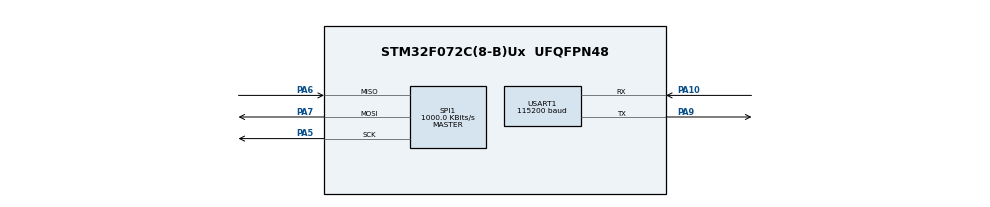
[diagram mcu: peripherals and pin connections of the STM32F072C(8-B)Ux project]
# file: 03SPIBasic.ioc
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Mcu.Family=STM32F0
Mcu.Name=STM32F072C(8-B)Ux
Mcu.Package=UFQFPN48
PA10.Mode=Asynchronous
PA10.Signal=USART1_RX
PA13.Mode=Serial_Wire
PA13.Signal=SYS_SWDIO
PA14.Mode=Serial_Wire
PA14.Signal=SYS_SWCLK
PA5.Mode=Full_Duplex_Master
PA5.Signal=SPI1_SCK
PA6.Mode=Full_Duplex_Master
PA6.Signal=SPI1_MISO
PA7.Mode=Full_Duplex_Master
PA7.Signal=SPI1_MOSI
PA9.Mode=Asynchronous
PA9.Signal=USART1_TX
ProjectManager.HeapSize=0x200
ProjectManager.StackSize=0x400
ProjectManager.TargetToolchain=CMake
RCC.SYSCLKFreq_VALUE=48000000
RCC.SYSCLKSource=RCC_SYSCLKSOURCE_HSI48
SPI1.BaudRatePrescaler=SPI_BAUDRATEPRESCALER_64
SPI1.CalculateBaudRate=1000.0 KBits/s
SPI1.Direction=SPI_DIRECTION_2LINES
SPI1.Mode=SPI_MODE_MASTER
SPI1.VirtualType=VM_MASTER
USART1.BaudRate=115200
USART1.VirtualMode-Asynchronous=VM_ASYNC
board=custom

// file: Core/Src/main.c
/* USER CODE BEGIN Header */
/**
  ******************************************************************************
  * @file           : main.c
  * @brief          : Main program body
  ******************************************************************************
  * @attention
  *
  * Copyright (c) 2026 STMicroelectronics.
  * All rights reserved.
  *
  * This software is licensed under terms that can be found in the LICENSE file
  * in the root directory of this software component.
  * If no LICENSE file comes with this software, it is provided AS-IS.
  *
  ******************************************************************************
  */
/* USER CODE END Header */
#include "main.h"

/* USER CODE BEGIN Includes */
#include <stdio.h>
#include <string.h>
/*
 * SPI1 全双工回环：主机、Mode 0（CPOL=0、CPHA=第一个边沿）、8 位、
 * MSB First、软件 NSS。HSI 8 MHz 经 8 分频后 SCK 约 1 MHz。
 * PA5=SCK、PA6=MISO、PA7=MOSI；测试时短接 PA6 与 PA7。
 */
/* USER CODE END Includes */

SPI_HandleTypeDef hspi1;

UART_HandleTypeDef huart1;

void SystemClock_Config(void);
static void MX_GPIO_Init(void);
static void MX_SPI1_Init(void);
static void MX_USART1_UART_Init(void);
/* USER CODE BEGIN PFP */
static void App_Init(void);
static void App_Loop(void);
/* USER CODE END PFP */

/* USER CODE BEGIN 0 */
/** @brief 通过 USART1 PA9 输出日志，阻塞发送超时为 100 ms。 */
int _write(int file,char *ptr,int len){(void)file;if(ptr==NULL||len<=0)return 0;return HAL_UART_Transmit(&huart1,(uint8_t*)ptr,(uint16_t)len,100U)==HAL_OK?len:-1;}
/** @brief SPI1 与 USART1 已由 CubeMX 初始化。 */
static void App_Init(void){}
/*
 * SPI 每移出一位也同时移入一位，所以 TX/RX 长度保持一致。
 * 100 ms 超时避免接线异常时永久等待；HAL 成功且八字节完全一致才 PASS。
 */
static void App_Loop(void){static const uint8_t tx[]={0x00,0x55,0xAA,0xFF,0x12,0x34,0x56,0x78};uint8_t rx[sizeof tx]={0};HAL_StatusTypeDef s=HAL_SPI_TransmitReceive(&hspi1,(uint8_t*)tx,rx,sizeof tx,100U);printf("\r\nSPI loopback test\r\nTX: 00 55 AA FF 12 34 56 78\r\nRX:");for(uint32_t i=0;i<sizeof rx;i++)printf(" %02X",rx[i]);printf("\r\nResult: %s\r\n",(s==HAL_OK&&memcmp(tx,rx,sizeof tx)==0)?"PASS":"FAIL");HAL_Delay(1000U);}
/* USER CODE END 0 */

int main(void)
{

  /* MCU Configuration--------------------------------------------------------*/

  /* Reset of all peripherals, Initializes the Flash interface and the Systick. */
  HAL_Init();

  /* Configure the system clock */
  SystemClock_Config();

  /* Initialize all configured peripherals */
  MX_GPIO_Init();
  MX_SPI1_Init();
  MX_USART1_UART_Init();
  /* USER CODE BEGIN 2 */
  App_Init();
  /* USER CODE END 2 */

  /* Infinite loop */
  /* USER CODE BEGIN WHILE */
  while (1)
  {
    App_Loop();
    /* USER CODE END WHILE */

  }
}

void SystemClock_Config(void)
{
  RCC_OscInitTypeDef RCC_OscInitStruct = {0};
  RCC_ClkInitTypeDef RCC_ClkInitStruct = {0};
  RCC_PeriphCLKInitTypeDef PeriphClkInit = {0};

  /** Initializes the RCC Oscillators according to the specified parameters
  * in the RCC_OscInitTypeDef structure.
  */
  RCC_OscInitStruct.OscillatorType = RCC_OSCILLATORTYPE_HSI;
  RCC_OscInitStruct.HSIState = RCC_HSI_ON;
  RCC_OscInitStruct.HSICalibrationValue = RCC_HSICALIBRATION_DEFAULT;
  RCC_OscInitStruct.PLL.PLLState = RCC_PLL_NONE;
  if (HAL_RCC_OscConfig(&RCC_OscInitStruct) != HAL_OK)
  {
    Error_Handler();
  }

  /** Initializes the CPU, AHB and APB buses clocks
  */
  RCC_ClkInitStruct.ClockType = RCC_CLOCKTYPE_HCLK|RCC_CLOCKTYPE_SYSCLK
                              |RCC_CLOCKTYPE_PCLK1;
  RCC_ClkInitStruct.SYSCLKSource = RCC_SYSCLKSOURCE_HSI;
  RCC_ClkInitStruct.AHBCLKDivider = RCC_SYSCLK_DIV1;
  RCC_ClkInitStruct.APB1CLKDivider = RCC_HCLK_DIV1;

  if (HAL_RCC_ClockConfig(&RCC_ClkInitStruct, FLASH_LATENCY_0) != HAL_OK)
  {
    Error_Handler();
  }
  PeriphClkInit.PeriphClockSelection = RCC_PERIPHCLK_USART1;
  PeriphClkInit.Usart1ClockSelection = RCC_USART1CLKSOURCE_PCLK1;
  if (HAL_RCCEx_PeriphCLKConfig(&PeriphClkInit) != HAL_OK)
  {
    Error_Handler();
  }
}

static void MX_SPI1_Init(void)
{

  /* SPI1 parameter configuration*/
  hspi1.Instance = SPI1;
  hspi1.Init.Mode = SPI_MODE_MASTER;
  hspi1.Init.Direction = SPI_DIRECTION_2LINES;
  hspi1.Init.DataSize = SPI_DATASIZE_4BIT;
  hspi1.Init.CLKPolarity = SPI_POLARITY_LOW;
  hspi1.Init.CLKPhase = SPI_PHASE_1EDGE;
  hspi1.Init.NSS = SPI_NSS_SOFT;
  hspi1.Init.BaudRatePrescaler = SPI_BAUDRATEPRESCALER_8;
  hspi1.Init.FirstBit = SPI_FIRSTBIT_MSB;
  hspi1.Init.TIMode = SPI_TIMODE_DISABLE;
  hspi1.Init.CRCCalculation = SPI_CRCCALCULATION_DISABLE;
  hspi1.Init.CRCPolynomial = 7;
  hspi1.Init.CRCLength = SPI_CRC_LENGTH_DATASIZE;
  hspi1.Init.NSSPMode = SPI_NSS_PULSE_ENABLE;
  if (HAL_SPI_Init(&hspi1) != HAL_OK)
  {
    Error_Handler();
  }

}

static void MX_USART1_UART_Init(void)
{

  huart1.Instance = USART1;
  huart1.Init.BaudRate = 115200;
  huart1.Init.WordLength = UART_WORDLENGTH_8B;
  huart1.Init.StopBits = UART_STOPBITS_1;
  huart1.Init.Parity = UART_PARITY_NONE;
  huart1.Init.Mode = UART_MODE_TX_RX;
  huart1.Init.HwFlowCtl = UART_HWCONTROL_NONE;
  huart1.Init.OverSampling = UART_OVERSAMPLING_16;
  huart1.Init.OneBitSampling = UART_ONE_BIT_SAMPLE_DISABLE;
  huart1.AdvancedInit.AdvFeatureInit = UART_ADVFEATURE_NO_INIT;
  if (HAL_UART_Init(&huart1) != HAL_OK)
  {
    Error_Handler();
  }

}

static void MX_GPIO_Init(void)
{

  /* GPIO Ports Clock Enable */
  __HAL_RCC_GPIOA_CLK_ENABLE();

}

void Error_Handler(void)
{
  __disable_irq();
  while (1)
  {
  }
}
